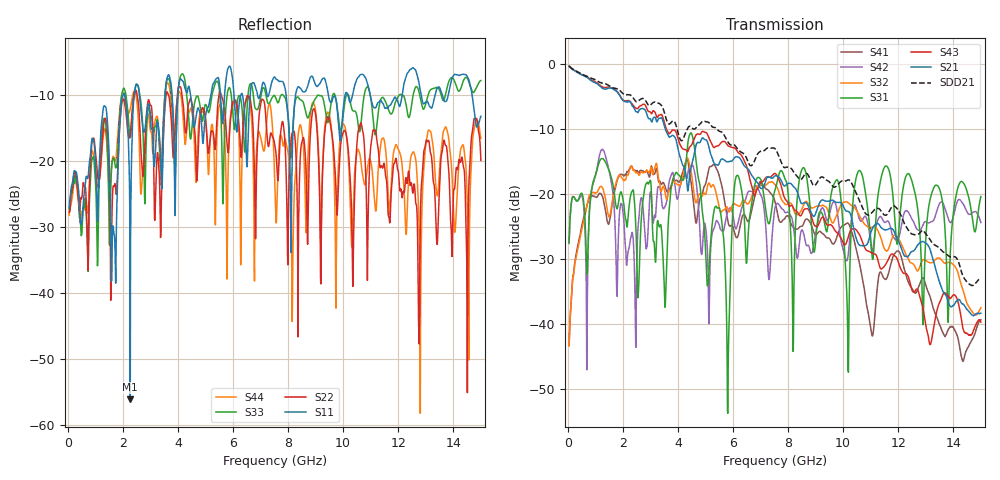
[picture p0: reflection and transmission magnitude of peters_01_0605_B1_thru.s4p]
! peters_01_0605 B1 channel thru response
#  HZ  S  RI  R  50
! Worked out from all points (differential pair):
!   1496 points, 50 MHz to 15 GHz, reference 50 ohm
!   strongest paths, dB at 50 MHz, 3.79 GHz, 7.53 GHz, 11.27 GHz, 15 GHz:
!     S21: -0.4, -11.0, -17.2, -24.6, -38.4
!     S43: -0.3, -10.2, -16.9, -30.4, -39.8
!     S31: -27.7, -18.2, -19.3, -20.1, -20.4
!     S32: -43.4, -18.5, -18.6, -25.8, -37.5
!     S42: -27.6, -16.8, -22.1, -23.9, -24.4
!     S41: -43.3, -18.3, -21.3, -33.3, -39.4
!   taken as a pair (ports 1,3 in; 2,4 out), SDD21 dB: -0.3, -8.9, -13.1, -22.3, -33.2
!   lowest |S11| = -56.0 dB at 2.27 GHz (marker M1), VSWR 1.00, Z = 50.1 - j0.135 ohm
!   |S11| at or under -10 dB: start of sweep to 2.009 GHz; 2.602 GHz to 3.537 GHz (935.6 MHz wide, 30.5 % of centre); 10.98 GHz to 12.14 GHz (1.168 GHz wide, 10.1 % of centre) (the widest 3 of 17)
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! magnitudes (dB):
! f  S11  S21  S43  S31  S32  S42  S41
! 50 MHz  -27.0  -0.4  -0.3  -27.7  -43.4  -27.6  -43.3
! 2.27 GHz  -56.0  -5.8  -5.8  -20.5  -15.9  -27.1  -15.9
! 4.49 GHz  -10.9  -15.8  -12.5  -10.7  -16.8  -15.8  -18.6
! 5.82 GHz  -5.9  -15.1  -12.6  -48.2  -22.4  -22.7  -24.3
! 6.15 GHz  -15.4  -14.3  -13.4  -17.2  -21.8  -25.0  -26.8
! 12.8 GHz  -9.3  -27.5  -36.1  -27.0  -31.0  -25.6  -33.7
! 15 GHz  -13.2  -38.4  -39.8  -20.4  -37.5  -24.4  -39.4
